VERSION 5.7 ;
  NOWIREEXTENSIONATPIN ON ;
  DIVIDERCHAR "/" ;
  BUSBITCHARS "[]" ;
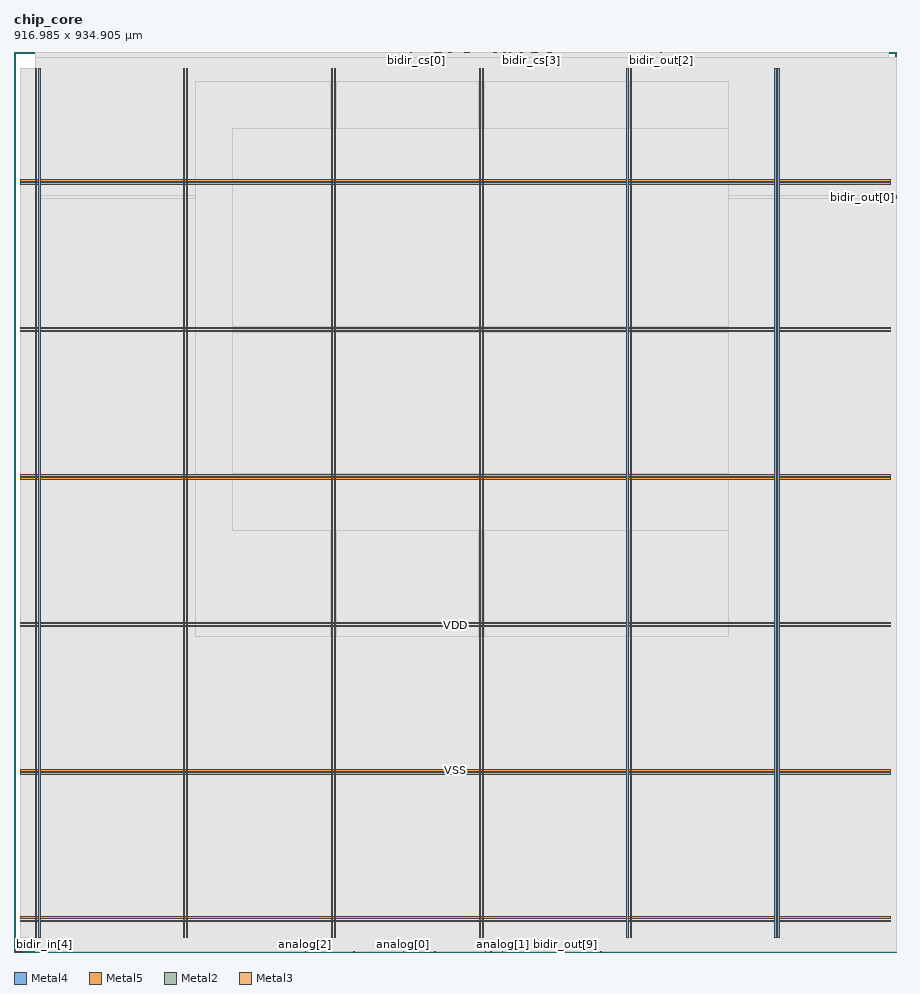
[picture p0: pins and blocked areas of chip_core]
MACRO chip_core
  CLASS BLOCK ;
  FOREIGN chip_core ;
  ORIGIN 0.000 0.000 ;
  SIZE 916.985 BY 934.905 ;
  PIN VDD
    DIRECTION INOUT ;
    USE POWER ;
    PORT
      LAYER Metal4 ;
        RECT 22.240 15.380 23.840 917.580 ;
    END
    PORT
      LAYER Metal4 ;
        RECT 175.840 15.380 177.440 917.580 ;
    END
    PORT
      LAYER Metal4 ;
        RECT 329.440 15.380 331.040 917.580 ;
    END
    PORT
      LAYER Metal4 ;
        RECT 483.040 15.380 484.640 917.580 ;
    END
    PORT
      LAYER Metal4 ;
        RECT 636.640 15.380 638.240 917.580 ;
    END
    PORT
      LAYER Metal4 ;
        RECT 790.240 15.380 791.840 917.580 ;
    END
    PORT
      LAYER Metal5 ;
        RECT 6.720 31.530 910.000 33.130 ;
    END
    PORT
      LAYER Metal5 ;
        RECT 6.720 184.710 910.000 186.310 ;
    END
    PORT
      LAYER Metal5 ;
        RECT 6.720 337.890 910.000 339.490 ;
    END
    PORT
      LAYER Metal5 ;
        RECT 6.720 491.070 910.000 492.670 ;
    END
    PORT
      LAYER Metal5 ;
        RECT 6.720 644.250 910.000 645.850 ;
    END
    PORT
      LAYER Metal5 ;
        RECT 6.720 797.430 910.000 799.030 ;
    END
  END VDD
  PIN VSS
    DIRECTION INOUT ;
    USE GROUND ;
    PORT
      LAYER Metal4 ;
        RECT 25.540 15.380 27.140 917.580 ;
    END
    PORT
      LAYER Metal4 ;
        RECT 179.140 15.380 180.740 917.580 ;
    END
    PORT
      LAYER Metal4 ;
        RECT 332.740 15.380 334.340 917.580 ;
    END
    PORT
      LAYER Metal4 ;
        RECT 486.340 15.380 487.940 917.580 ;
    END
    PORT
      LAYER Metal4 ;
        RECT 639.940 15.380 641.540 917.580 ;
    END
    PORT
      LAYER Metal4 ;
        RECT 793.540 15.380 795.140 917.580 ;
    END
    PORT
      LAYER Metal5 ;
        RECT 6.720 34.830 910.000 36.430 ;
    END
    PORT
      LAYER Metal5 ;
        RECT 6.720 188.010 910.000 189.610 ;
    END
    PORT
      LAYER Metal5 ;
        RECT 6.720 341.190 910.000 342.790 ;
    END
    PORT
      LAYER Metal5 ;
        RECT 6.720 494.370 910.000 495.970 ;
    END
    PORT
      LAYER Metal5 ;
        RECT 6.720 647.550 910.000 649.150 ;
    END
    PORT
      LAYER Metal5 ;
        RECT 6.720 800.730 910.000 802.330 ;
    END
  END VSS
  PIN analog[0]
    DIRECTION INOUT ;
    USE SIGNAL ;
    ANTENNAGATEAREA 0.741000 ;
    PORT
      LAYER Metal2 ;
        RECT 404.320 0.000 404.880 0.560 ;
    END
  END analog[0]
  PIN analog[1]
    DIRECTION INOUT ;
    USE SIGNAL ;
    ANTENNAGATEAREA 0.741000 ;
    PORT
      LAYER Metal2 ;
        RECT 507.360 0.000 507.920 0.560 ;
    END
  END analog[1]
  PIN analog[2]
    DIRECTION INOUT ;
    USE SIGNAL ;
    PORT
      LAYER Metal2 ;
        RECT 302.400 0.000 302.960 0.560 ;
    END
  END analog[2]
  PIN analog[3]
    DIRECTION INOUT ;
    USE SIGNAL ;
    ANTENNAGATEAREA 0.741000 ;
    PORT
      LAYER Metal2 ;
        RECT 609.280 0.000 609.840 0.560 ;
    END
  END analog[3]
  PIN bidir_cs[0]
    DIRECTION OUTPUT ;
    USE SIGNAL ;
    ANTENNADIFFAREA 0.536800 ;
    PORT
      LAYER Metal2 ;
        RECT 417.760 934.345 418.320 934.905 ;
    END
  END bidir_cs[0]
  PIN bidir_cs[1]
    DIRECTION OUTPUT ;
    USE SIGNAL ;
    ANTENNADIFFAREA 0.536800 ;
    PORT
      LAYER Metal2 ;
        RECT 435.680 934.345 436.240 934.905 ;
    END
  END bidir_cs[1]
  PIN bidir_cs[2]
    DIRECTION OUTPUT ;
    USE SIGNAL ;
    ANTENNADIFFAREA 0.536800 ;
    PORT
      LAYER Metal2 ;
        RECT 451.360 934.345 451.920 934.905 ;
    END
  END bidir_cs[2]
  PIN bidir_cs[3]
    DIRECTION OUTPUT ;
    USE SIGNAL ;
    ANTENNADIFFAREA 0.360800 ;
    PORT
      LAYER Metal2 ;
        RECT 537.600 934.345 538.160 934.905 ;
    END
  END bidir_cs[3]
  PIN bidir_cs[4]
    DIRECTION OUTPUT ;
    USE SIGNAL ;
    ANTENNADIFFAREA 0.360800 ;
    PORT
      LAYER Metal2 ;
        RECT 509.600 934.345 510.160 934.905 ;
    END
  END bidir_cs[4]
  PIN bidir_cs[5]
    DIRECTION OUTPUT ;
    USE SIGNAL ;
    ANTENNADIFFAREA 0.360800 ;
    PORT
      LAYER Metal2 ;
        RECT 445.760 934.345 446.320 934.905 ;
    END
  END bidir_cs[5]
  PIN bidir_cs[6]
    DIRECTION OUTPUT ;
    USE SIGNAL ;
    ANTENNADIFFAREA 0.360800 ;
    PORT
      LAYER Metal2 ;
        RECT 539.840 934.345 540.400 934.905 ;
    END
  END bidir_cs[6]
  PIN bidir_cs[7]
    DIRECTION OUTPUT ;
    USE SIGNAL ;
    ANTENNADIFFAREA 0.360800 ;
    PORT
      LAYER Metal2 ;
        RECT 444.640 934.345 445.200 934.905 ;
    END
  END bidir_cs[7]
  PIN bidir_cs[8]
    DIRECTION OUTPUT ;
    USE SIGNAL ;
    ANTENNADIFFAREA 0.360800 ;
    PORT
      LAYER Metal2 ;
        RECT 508.480 934.345 509.040 934.905 ;
    END
  END bidir_cs[8]
  PIN bidir_cs[9]
    DIRECTION OUTPUT ;
    USE SIGNAL ;
    ANTENNADIFFAREA 0.360800 ;
    PORT
      LAYER Metal2 ;
        RECT 548.800 934.345 549.360 934.905 ;
    END
  END bidir_cs[9]
  PIN bidir_ie[0]
    DIRECTION OUTPUT ;
    USE SIGNAL ;
    ANTENNADIFFAREA 0.536800 ;
    PORT
      LAYER Metal2 ;
        RECT 563.360 934.345 563.920 934.905 ;
    END
  END bidir_ie[0]
  PIN bidir_ie[1]
    DIRECTION OUTPUT ;
    USE SIGNAL ;
    ANTENNADIFFAREA 0.536800 ;
    PORT
      LAYER Metal2 ;
        RECT 443.520 934.345 444.080 934.905 ;
    END
  END bidir_ie[1]
  PIN bidir_ie[2]
    DIRECTION OUTPUT ;
    USE SIGNAL ;
    ANTENNADIFFAREA 0.536800 ;
    PORT
      LAYER Metal2 ;
        RECT 540.960 934.345 541.520 934.905 ;
    END
  END bidir_ie[2]
  PIN bidir_ie[3]
    DIRECTION OUTPUT ;
    USE SIGNAL ;
    ANTENNADIFFAREA 0.360800 ;
    PORT
      LAYER Metal2 ;
        RECT 502.880 934.345 503.440 934.905 ;
    END
  END bidir_ie[3]
  PIN bidir_ie[4]
    DIRECTION OUTPUT ;
    USE SIGNAL ;
    ANTENNADIFFAREA 0.360800 ;
    PORT
      LAYER Metal2 ;
        RECT 478.240 934.345 478.800 934.905 ;
    END
  END bidir_ie[4]
  PIN bidir_ie[5]
    DIRECTION OUTPUT ;
    USE SIGNAL ;
    ANTENNADIFFAREA 0.360800 ;
    PORT
      LAYER Metal2 ;
        RECT 463.680 934.345 464.240 934.905 ;
    END
  END bidir_ie[5]
  PIN bidir_ie[6]
    DIRECTION OUTPUT ;
    USE SIGNAL ;
    ANTENNADIFFAREA 0.360800 ;
    PORT
      LAYER Metal2 ;
        RECT 464.800 934.345 465.360 934.905 ;
    END
  END bidir_ie[6]
  PIN bidir_ie[7]
    DIRECTION OUTPUT ;
    USE SIGNAL ;
    ANTENNADIFFAREA 0.360800 ;
    PORT
      LAYER Metal2 ;
        RECT 556.640 934.345 557.200 934.905 ;
    END
  END bidir_ie[7]
  PIN bidir_ie[8]
    DIRECTION OUTPUT ;
    USE SIGNAL ;
    ANTENNADIFFAREA 0.360800 ;
    PORT
      LAYER Metal2 ;
        RECT 542.080 934.345 542.640 934.905 ;
    END
  END bidir_ie[8]
  PIN bidir_ie[9]
    DIRECTION OUTPUT ;
    USE SIGNAL ;
    ANTENNADIFFAREA 0.360800 ;
    PORT
      LAYER Metal2 ;
        RECT 536.480 934.345 537.040 934.905 ;
    END
  END bidir_ie[9]
  PIN bidir_in[0]
    DIRECTION INPUT ;
    USE SIGNAL ;
    ANTENNAGATEAREA 0.498500 ;
    PORT
      LAYER Metal2 ;
        RECT 436.800 934.345 437.360 934.905 ;
    END
  END bidir_in[0]
  PIN bidir_in[1]
    DIRECTION INPUT ;
    USE SIGNAL ;
    ANTENNAGATEAREA 0.498500 ;
    PORT
      LAYER Metal2 ;
        RECT 439.040 934.345 439.600 934.905 ;
    END
  END bidir_in[1]
  PIN bidir_in[2]
    DIRECTION INPUT ;
    USE SIGNAL ;
    ANTENNAGATEAREA 0.498500 ;
    PORT
      LAYER Metal2 ;
        RECT 377.440 934.345 378.000 934.905 ;
    END
  END bidir_in[2]
  PIN bidir_in[3]
    DIRECTION INPUT ;
    USE SIGNAL ;
    PORT
      LAYER Metal2 ;
        RECT 1.120 0.000 1.680 0.560 ;
    END
  END bidir_in[3]
  PIN bidir_in[4]
    DIRECTION INPUT ;
    USE SIGNAL ;
    PORT
      LAYER Metal2 ;
        RECT 2.240 0.000 2.800 0.560 ;
    END
  END bidir_in[4]
  PIN bidir_in[5]
    DIRECTION INPUT ;
    USE SIGNAL ;
    PORT
      LAYER Metal2 ;
        RECT 3.360 0.000 3.920 0.560 ;
    END
  END bidir_in[5]
  PIN bidir_in[6]
    DIRECTION INPUT ;
    USE SIGNAL ;
    PORT
      LAYER Metal2 ;
        RECT 4.480 0.000 5.040 0.560 ;
    END
  END bidir_in[6]
  PIN bidir_in[7]
    DIRECTION INPUT ;
    USE SIGNAL ;
    PORT
      LAYER Metal2 ;
        RECT 5.600 0.000 6.160 0.560 ;
    END
  END bidir_in[7]
  PIN bidir_in[8]
    DIRECTION INPUT ;
    USE SIGNAL ;
    PORT
      LAYER Metal2 ;
        RECT 6.720 0.000 7.280 0.560 ;
    END
  END bidir_in[8]
  PIN bidir_in[9]
    DIRECTION INPUT ;
    USE SIGNAL ;
    PORT
      LAYER Metal2 ;
        RECT 7.840 0.000 8.400 0.560 ;
    END
  END bidir_in[9]
  PIN bidir_oe[0]
    DIRECTION OUTPUT ;
    USE SIGNAL ;
    ANTENNADIFFAREA 0.360800 ;
    PORT
      LAYER Metal2 ;
        RECT 516.320 934.345 516.880 934.905 ;
    END
  END bidir_oe[0]
  PIN bidir_oe[1]
    DIRECTION OUTPUT ;
    USE SIGNAL ;
    ANTENNADIFFAREA 0.360800 ;
    PORT
      LAYER Metal2 ;
        RECT 526.400 934.345 526.960 934.905 ;
    END
  END bidir_oe[1]
  PIN bidir_oe[2]
    DIRECTION OUTPUT ;
    USE SIGNAL ;
    ANTENNADIFFAREA 0.360800 ;
    PORT
      LAYER Metal2 ;
        RECT 557.760 934.345 558.320 934.905 ;
    END
  END bidir_oe[2]
  PIN bidir_oe[3]
    DIRECTION OUTPUT ;
    USE SIGNAL ;
    ANTENNADIFFAREA 1.182800 ;
    PORT
      LAYER Metal2 ;
        RECT 498.400 934.345 498.960 934.905 ;
    END
  END bidir_oe[3]
  PIN bidir_oe[4]
    DIRECTION OUTPUT ;
    USE SIGNAL ;
    ANTENNADIFFAREA 0.536800 ;
    PORT
      LAYER Metal2 ;
        RECT 500.640 934.345 501.200 934.905 ;
    END
  END bidir_oe[4]
  PIN bidir_oe[5]
    DIRECTION OUTPUT ;
    USE SIGNAL ;
    ANTENNADIFFAREA 0.536800 ;
    PORT
      LAYER Metal2 ;
        RECT 446.880 934.345 447.440 934.905 ;
    END
  END bidir_oe[5]
  PIN bidir_oe[6]
    DIRECTION OUTPUT ;
    USE SIGNAL ;
    ANTENNADIFFAREA 0.536800 ;
    PORT
      LAYER Metal2 ;
        RECT 474.880 934.345 475.440 934.905 ;
    END
  END bidir_oe[6]
  PIN bidir_oe[7]
    DIRECTION OUTPUT ;
    USE SIGNAL ;
    ANTENNADIFFAREA 0.536800 ;
    PORT
      LAYER Metal2 ;
        RECT 450.240 934.345 450.800 934.905 ;
    END
  END bidir_oe[7]
  PIN bidir_oe[8]
    DIRECTION OUTPUT ;
    USE SIGNAL ;
    ANTENNADIFFAREA 0.536800 ;
    PORT
      LAYER Metal2 ;
        RECT 554.400 934.345 554.960 934.905 ;
    END
  END bidir_oe[8]
  PIN bidir_oe[9]
    DIRECTION OUTPUT ;
    USE SIGNAL ;
    ANTENNADIFFAREA 0.536800 ;
    PORT
      LAYER Metal2 ;
        RECT 468.160 934.345 468.720 934.905 ;
    END
  END bidir_oe[9]
  PIN bidir_out[0]
    DIRECTION OUTPUT ;
    USE SIGNAL ;
    ANTENNADIFFAREA 1.182800 ;
    PORT
      LAYER Metal3 ;
        RECT 916.425 784.000 916.985 784.560 ;
    END
  END bidir_out[0]
  PIN bidir_out[1]
    DIRECTION OUTPUT ;
    USE SIGNAL ;
    ANTENNADIFFAREA 1.182800 ;
    PORT
      LAYER Metal3 ;
        RECT 916.425 785.120 916.985 785.680 ;
    END
  END bidir_out[1]
  PIN bidir_out[2]
    DIRECTION OUTPUT ;
    USE SIGNAL ;
    ANTENNADIFFAREA 1.182800 ;
    PORT
      LAYER Metal2 ;
        RECT 672.000 934.345 672.560 934.905 ;
    END
  END bidir_out[2]
  PIN bidir_out[3]
    DIRECTION OUTPUT ;
    USE SIGNAL ;
    ANTENNADIFFAREA 1.182800 ;
    PORT
      LAYER Metal2 ;
        RECT 505.120 934.345 505.680 934.905 ;
    END
  END bidir_out[3]
  PIN bidir_out[4]
    DIRECTION OUTPUT ;
    USE SIGNAL ;
    ANTENNADIFFAREA 1.182800 ;
    PORT
      LAYER Metal2 ;
        RECT 436.800 0.000 437.360 0.560 ;
    END
  END bidir_out[4]
  PIN bidir_out[5]
    DIRECTION OUTPUT ;
    USE SIGNAL ;
    ANTENNADIFFAREA 1.182800 ;
    PORT
      LAYER Metal2 ;
        RECT 427.840 0.000 428.400 0.560 ;
    END
  END bidir_out[5]
  PIN bidir_out[6]
    DIRECTION OUTPUT ;
    USE SIGNAL ;
    ANTENNADIFFAREA 1.182800 ;
    PORT
      LAYER Metal2 ;
        RECT 495.040 0.000 495.600 0.560 ;
    END
  END bidir_out[6]
  PIN bidir_out[7]
    DIRECTION OUTPUT ;
    USE SIGNAL ;
    ANTENNADIFFAREA 1.182800 ;
    PORT
      LAYER Metal2 ;
        RECT 489.440 0.000 490.000 0.560 ;
    END
  END bidir_out[7]
  PIN bidir_out[8]
    DIRECTION OUTPUT ;
    USE SIGNAL ;
    ANTENNADIFFAREA 1.182800 ;
    PORT
      LAYER Metal2 ;
        RECT 352.800 0.000 353.360 0.560 ;
    END
  END bidir_out[8]
  PIN bidir_out[9]
    DIRECTION OUTPUT ;
    USE SIGNAL ;
    ANTENNADIFFAREA 1.182800 ;
    PORT
      LAYER Metal2 ;
        RECT 572.320 0.000 572.880 0.560 ;
    END
  END bidir_out[9]
  PIN bidir_pd[0]
    DIRECTION OUTPUT ;
    USE SIGNAL ;
    ANTENNADIFFAREA 0.360800 ;
    PORT
      LAYER Metal2 ;
        RECT 477.120 934.345 477.680 934.905 ;
    END
  END bidir_pd[0]
  PIN bidir_pd[1]
    DIRECTION OUTPUT ;
    USE SIGNAL ;
    ANTENNADIFFAREA 0.360800 ;
    PORT
      LAYER Metal2 ;
        RECT 506.240 934.345 506.800 934.905 ;
    END
  END bidir_pd[1]
  PIN bidir_pd[2]
    DIRECTION OUTPUT ;
    USE SIGNAL ;
    ANTENNADIFFAREA 0.360800 ;
    PORT
      LAYER Metal2 ;
        RECT 517.440 934.345 518.000 934.905 ;
    END
  END bidir_pd[2]
  PIN bidir_pd[3]
    DIRECTION OUTPUT ;
    USE SIGNAL ;
    ANTENNADIFFAREA 0.360800 ;
    PORT
      LAYER Metal2 ;
        RECT 504.000 934.345 504.560 934.905 ;
    END
  END bidir_pd[3]
  PIN bidir_pd[4]
    DIRECTION OUTPUT ;
    USE SIGNAL ;
    ANTENNADIFFAREA 0.360800 ;
    PORT
      LAYER Metal2 ;
        RECT 453.600 934.345 454.160 934.905 ;
    END
  END bidir_pd[4]
  PIN bidir_pd[5]
    DIRECTION OUTPUT ;
    USE SIGNAL ;
    ANTENNADIFFAREA 0.360800 ;
    PORT
      LAYER Metal2 ;
        RECT 441.280 934.345 441.840 934.905 ;
    END
  END bidir_pd[5]
  PIN bidir_pd[6]
    DIRECTION OUTPUT ;
    USE SIGNAL ;
    ANTENNADIFFAREA 0.360800 ;
    PORT
      LAYER Metal2 ;
        RECT 449.120 934.345 449.680 934.905 ;
    END
  END bidir_pd[6]
  PIN bidir_pd[7]
    DIRECTION OUTPUT ;
    USE SIGNAL ;
    ANTENNADIFFAREA 0.360800 ;
    PORT
      LAYER Metal2 ;
        RECT 507.360 934.345 507.920 934.905 ;
    END
  END bidir_pd[7]
  PIN bidir_pd[8]
    DIRECTION OUTPUT ;
    USE SIGNAL ;
    ANTENNADIFFAREA 0.360800 ;
    PORT
      LAYER Metal2 ;
        RECT 476.000 934.345 476.560 934.905 ;
    END
  END bidir_pd[8]
  PIN bidir_pd[9]
    DIRECTION OUTPUT ;
    USE SIGNAL ;
    ANTENNADIFFAREA 0.360800 ;
    PORT
      LAYER Metal2 ;
        RECT 437.920 934.345 438.480 934.905 ;
    END
  END bidir_pd[9]
  PIN bidir_pu[0]
    DIRECTION OUTPUT ;
    USE SIGNAL ;
    ANTENNADIFFAREA 0.536800 ;
    PORT
      LAYER Metal2 ;
        RECT 473.760 934.345 474.320 934.905 ;
    END
  END bidir_pu[0]
  PIN bidir_pu[1]
    DIRECTION OUTPUT ;
    USE SIGNAL ;
    ANTENNADIFFAREA 0.360800 ;
    PORT
      LAYER Metal2 ;
        RECT 469.280 934.345 469.840 934.905 ;
    END
  END bidir_pu[1]
  PIN bidir_pu[2]
    DIRECTION OUTPUT ;
    USE SIGNAL ;
    ANTENNADIFFAREA 0.360800 ;
    PORT
      LAYER Metal2 ;
        RECT 543.200 934.345 543.760 934.905 ;
    END
  END bidir_pu[2]
  PIN bidir_pu[3]
    DIRECTION OUTPUT ;
    USE SIGNAL ;
    ANTENNADIFFAREA 0.360800 ;
    PORT
      LAYER Metal2 ;
        RECT 501.760 934.345 502.320 934.905 ;
    END
  END bidir_pu[3]
  PIN bidir_pu[4]
    DIRECTION OUTPUT ;
    USE SIGNAL ;
    ANTENNADIFFAREA 0.360800 ;
    PORT
      LAYER Metal2 ;
        RECT 412.160 934.345 412.720 934.905 ;
    END
  END bidir_pu[4]
  PIN bidir_pu[5]
    DIRECTION OUTPUT ;
    USE SIGNAL ;
    ANTENNADIFFAREA 0.360800 ;
    PORT
      LAYER Metal2 ;
        RECT 462.560 934.345 463.120 934.905 ;
    END
  END bidir_pu[5]
  PIN bidir_pu[6]
    DIRECTION OUTPUT ;
    USE SIGNAL ;
    ANTENNADIFFAREA 0.360800 ;
    PORT
      LAYER Metal2 ;
        RECT 472.640 934.345 473.200 934.905 ;
    END
  END bidir_pu[6]
  PIN bidir_pu[7]
    DIRECTION OUTPUT ;
    USE SIGNAL ;
    ANTENNADIFFAREA 0.360800 ;
    PORT
      LAYER Metal2 ;
        RECT 452.480 934.345 453.040 934.905 ;
    END
  END bidir_pu[7]
  PIN bidir_pu[8]
    DIRECTION OUTPUT ;
    USE SIGNAL ;
    ANTENNADIFFAREA 0.360800 ;
    PORT
      LAYER Metal2 ;
        RECT 471.520 934.345 472.080 934.905 ;
    END
  END bidir_pu[8]
  PIN bidir_pu[9]
    DIRECTION OUTPUT ;
    USE SIGNAL ;
    ANTENNADIFFAREA 0.360800 ;
    PORT
      LAYER Metal2 ;
        RECT 538.720 934.345 539.280 934.905 ;
    END
  END bidir_pu[9]
  PIN bidir_sl[0]
    DIRECTION OUTPUT ;
    USE SIGNAL ;
    ANTENNADIFFAREA 0.360800 ;
    PORT
      LAYER Metal2 ;
        RECT 492.800 934.345 493.360 934.905 ;
    END
  END bidir_sl[0]
  PIN bidir_sl[1]
    DIRECTION OUTPUT ;
    USE SIGNAL ;
    ANTENNADIFFAREA 0.360800 ;
    PORT
      LAYER Metal2 ;
        RECT 520.800 934.345 521.360 934.905 ;
    END
  END bidir_sl[1]
  PIN bidir_sl[2]
    DIRECTION OUTPUT ;
    USE SIGNAL ;
    ANTENNADIFFAREA 0.360800 ;
    PORT
      LAYER Metal2 ;
        RECT 545.440 934.345 546.000 934.905 ;
    END
  END bidir_sl[2]
  PIN bidir_sl[3]
    DIRECTION OUTPUT ;
    USE SIGNAL ;
    ANTENNADIFFAREA 0.536800 ;
    PORT
      LAYER Metal2 ;
        RECT 532.000 934.345 532.560 934.905 ;
    END
  END bidir_sl[3]
  PIN bidir_sl[4]
    DIRECTION OUTPUT ;
    USE SIGNAL ;
    ANTENNADIFFAREA 0.360800 ;
    PORT
      LAYER Metal2 ;
        RECT 442.400 934.345 442.960 934.905 ;
    END
  END bidir_sl[4]
  PIN bidir_sl[5]
    DIRECTION OUTPUT ;
    USE SIGNAL ;
    ANTENNADIFFAREA 0.360800 ;
    PORT
      LAYER Metal2 ;
        RECT 499.520 934.345 500.080 934.905 ;
    END
  END bidir_sl[5]
  PIN bidir_sl[6]
    DIRECTION OUTPUT ;
    USE SIGNAL ;
    ANTENNADIFFAREA 0.360800 ;
    PORT
      LAYER Metal2 ;
        RECT 527.520 934.345 528.080 934.905 ;
    END
  END bidir_sl[6]
  PIN bidir_sl[7]
    DIRECTION OUTPUT ;
    USE SIGNAL ;
    ANTENNADIFFAREA 0.360800 ;
    PORT
      LAYER Metal2 ;
        RECT 448.000 934.345 448.560 934.905 ;
    END
  END bidir_sl[7]
  PIN bidir_sl[8]
    DIRECTION OUTPUT ;
    USE SIGNAL ;
    ANTENNADIFFAREA 0.360800 ;
    PORT
      LAYER Metal2 ;
        RECT 515.200 934.345 515.760 934.905 ;
    END
  END bidir_sl[8]
  PIN bidir_sl[9]
    DIRECTION OUTPUT ;
    USE SIGNAL ;
    ANTENNADIFFAREA 0.360800 ;
    PORT
      LAYER Metal2 ;
        RECT 470.400 934.345 470.960 934.905 ;
    END
  END bidir_sl[9]
  PIN clk
    DIRECTION INPUT ;
    USE SIGNAL ;
    ANTENNAGATEAREA 9.476000 ;
    PORT
      LAYER Metal2 ;
        RECT 691.040 934.345 691.600 934.905 ;
    END
  END clk
  PIN input_in
    DIRECTION INPUT ;
    USE SIGNAL ;
    ANTENNAGATEAREA 0.498500 ;
    PORT
      LAYER Metal3 ;
        RECT 916.425 782.880 916.985 783.440 ;
    END
  END input_in
  PIN input_pd
    DIRECTION OUTPUT ;
    USE SIGNAL ;
    ANTENNADIFFAREA 0.360800 ;
    PORT
      LAYER Metal2 ;
        RECT 530.880 934.345 531.440 934.905 ;
    END
  END input_pd
  PIN input_pu
    DIRECTION OUTPUT ;
    USE SIGNAL ;
    ANTENNADIFFAREA 0.360800 ;
    PORT
      LAYER Metal2 ;
        RECT 440.160 934.345 440.720 934.905 ;
    END
  END input_pu
  PIN rst_n
    DIRECTION INPUT ;
    USE SIGNAL ;
    ANTENNAGATEAREA 0.498500 ;
    PORT
      LAYER Metal2 ;
        RECT 689.920 934.345 690.480 934.905 ;
    END
  END rst_n
  OBS
      LAYER Nwell ;
        RECT 6.290 15.250 910.430 917.710 ;
      LAYER Metal1 ;
        RECT 6.720 15.380 910.000 917.580 ;
      LAYER Metal2 ;
        RECT 22.380 934.045 377.140 934.765 ;
        RECT 378.300 934.045 411.860 934.765 ;
        RECT 413.020 934.045 417.460 934.765 ;
        RECT 418.620 934.045 435.380 934.765 ;
        RECT 454.460 934.045 462.260 934.765 ;
        RECT 465.660 934.045 467.860 934.765 ;
        RECT 479.100 934.045 492.500 934.765 ;
        RECT 493.660 934.045 498.100 934.765 ;
        RECT 510.460 934.045 514.900 934.765 ;
        RECT 518.300 934.045 520.500 934.765 ;
        RECT 521.660 934.045 526.100 934.765 ;
        RECT 528.380 934.045 530.580 934.765 ;
        RECT 532.860 934.045 536.180 934.765 ;
        RECT 544.060 934.045 545.140 934.765 ;
        RECT 546.300 934.045 548.500 934.765 ;
        RECT 549.660 934.045 554.100 934.765 ;
        RECT 555.260 934.045 556.340 934.765 ;
        RECT 558.620 934.045 563.060 934.765 ;
        RECT 564.220 934.045 671.700 934.765 ;
        RECT 672.860 934.045 689.620 934.765 ;
        RECT 691.900 934.045 908.180 934.765 ;
        RECT 22.380 0.860 908.180 934.045 ;
        RECT 22.380 0.090 302.100 0.860 ;
        RECT 303.260 0.090 352.500 0.860 ;
        RECT 353.660 0.090 404.020 0.860 ;
        RECT 405.180 0.090 427.540 0.860 ;
        RECT 428.700 0.090 436.500 0.860 ;
        RECT 437.660 0.090 489.140 0.860 ;
        RECT 490.300 0.090 494.740 0.860 ;
        RECT 495.900 0.090 507.060 0.860 ;
        RECT 508.220 0.090 572.020 0.860 ;
        RECT 573.180 0.090 608.980 0.860 ;
        RECT 610.140 0.090 908.180 0.860 ;
      LAYER Metal3 ;
        RECT 22.330 785.980 916.425 929.460 ;
        RECT 22.330 782.580 916.125 785.980 ;
        RECT 22.330 0.140 916.425 782.580 ;
      LAYER Metal4 ;
        RECT 188.300 327.690 329.140 904.310 ;
        RECT 331.340 327.690 332.440 904.310 ;
        RECT 334.640 327.690 482.740 904.310 ;
        RECT 484.940 327.690 486.040 904.310 ;
        RECT 488.240 327.690 636.340 904.310 ;
        RECT 638.540 327.690 639.640 904.310 ;
        RECT 641.840 327.690 742.420 904.310 ;
      LAYER Metal5 ;
        RECT 227.420 802.930 742.500 855.670 ;
        RECT 227.420 799.630 742.500 800.130 ;
        RECT 227.420 649.750 742.500 796.830 ;
        RECT 227.420 646.450 742.500 646.950 ;
        RECT 227.420 496.570 742.500 643.650 ;
        RECT 227.420 493.270 742.500 493.770 ;
        RECT 227.420 437.630 742.500 490.470 ;
  END
END chip_core
END LIBRARY

